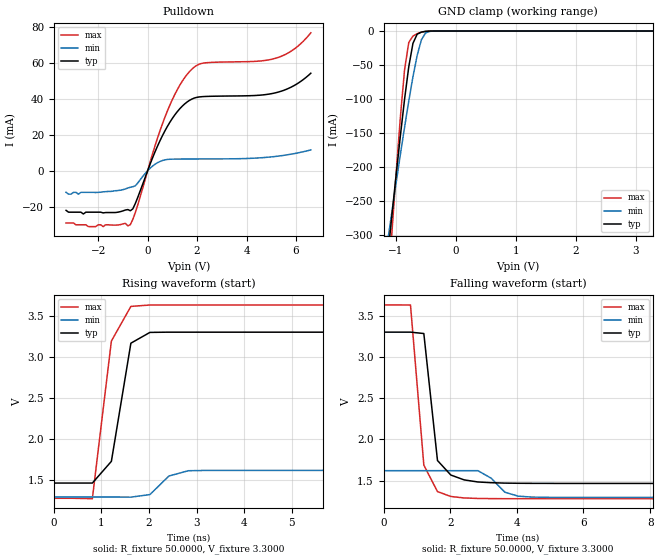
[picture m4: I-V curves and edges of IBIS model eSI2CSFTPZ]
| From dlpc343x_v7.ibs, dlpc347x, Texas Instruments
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[Model]  eSI2CSFTPZ
Model_type I/O_open_drain
Polarity   Non-Inverting
Enable   Active-High
Vinl =   0.0V
Vinh =   3.3000V
Vmeas =  1.6500V
Rref =   500.0000
Vref =   3.3V
C_comp   2.1049pF   1.8316pF   1.9628pF
[Temperature Range]   25.0000   0.1050k   -30.0000
[Pullup Reference]   3.3000V   1.6200V   3.6300V
[Pulldown Reference]   0.0V   0.0V   0.0V
[POWER Clamp Reference]   3.3000V   1.6200V   3.6300V
[GND Clamp Reference]   0.0V   0.0V   0.0V
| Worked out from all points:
|   slope of the pulldown table from 0 to 0.495 V, typ, clamps not added: 29.9 ohm
|   GND clamp passes 1 mA (typ) near -0.53 V on its own axis
|   rising waveform, R_fixture 50.0000, V_fixture 3.3000: 20-80 % time 314ps typ, 364ps min, 294ps max; typ from 1.47 V to 3.3 V
|   falling waveform, R_fixture 50.0000, V_fixture 3.3000: 20-80 % time 293ps typ, 521ps min, 290ps max; typ from 3.3 V to 1.47 V
[Pulldown]
|Voltage   I(typ)   I(min)   I(max)
-3.3V     -22mA      -12mA      -29mA
-2.6V     -24mA      -12mA      -30mA
-700mV    -22.2mA    -9.18mA    -29.9mA
-500mV    -18.24mA   -8.389mA   -23.3mA
200mV     7.182mA    2.577mA    9.472mA
800mV     24.62mA    6.256mA    33.2mA
1.4V      35.83mA    6.49mA     49.68mA
1.9V      40.39mA    6.522mA    57.65mA
2.3V      41.18mA    6.538mA    59.81mA
5.2V      43.33mA    7.976mA    62.52mA
5.9V      47.07mA    9.425mA    67.23mA
6.6V      54.11mA    11.53mA    76.52mA
[GND_clamp]
|Voltage   I(typ)   I(min)   I(max)
-3.3V     -2.377A    -1.75A     -3.463A
-1.13V    -331.8mA   -309mA     -386.6mA
-1.06V    -271.2mA   -265.9mA   -296.4mA
-920mV    -154.8mA   -182.1mA   -127.4mA
-850mV    -100.8mA   -141.9mA   -57.27mA
-780mV    -52.76mA   -103.3mA   -16.94mA
-710mV    -18.12mA   -67.29mA   -7.429mA
-640mV    -4.691mA   -35.84mA   -3.902mA
-570mV    -1.611mA   -13.05mA   -1.639mA
-500mV    -496.8uA   -2.841mA   -454.2uA
-430mV    -94.47uA   -468.6uA   -64.45uA
3.28V     437.5pA    3.787nA    75.03pA
[Ramp]
| variable   typ   min   max
dV/dt_r  1.1010/0.3067n   0.1944/0.3629n   1.4100/0.2944n
dV/dt_f  1.1010/0.2860n   0.1944/0.5109n   1.4100/0.2904n
R_load = 50.0000
[Rising Waveform]
R_fixture= 50.0000
V_fixture= 3.3000
V_fixture_min= 1.6200
V_fixture_max= 3.6300
|time   V(typ)   V(min)   V(max)
0s        1.465V     1.296V     1.28V
810ps     1.465V     1.296V     1.275V
1.21ns    1.729V     1.296V     3.191V
1.62ns    3.165V     1.294V     3.612V
2.02ns    3.296V     1.325V     3.629V
2.42ns    3.299V     1.551V     3.629V
2.83ns    3.299V     1.615V     3.629V
3.23ns    3.299V     1.619V     3.629V
40ns      3.3V       1.62V      3.63V
[Falling Waveform]
R_fixture= 50.0000
V_fixture= 3.3000
V_fixture_min= 1.6200
V_fixture_max= 3.6300
|time   V(typ)   V(min)   V(max)
0s        3.3V       1.62V      3.63V
810ps     3.3V       1.62V      3.629V
1.21ns    3.283V     1.62V      1.687V
1.62ns    1.743V     1.62V      1.366V
2.02ns    1.567V     1.62V      1.307V
2.83ns    1.483V     1.62V      1.283V
3.23ns    1.474V     1.529V     1.281V
3.64ns    1.469V     1.359V     1.28V
4.44ns    1.466V     1.3V       1.28V
40ns      1.465V     1.296V     1.28V
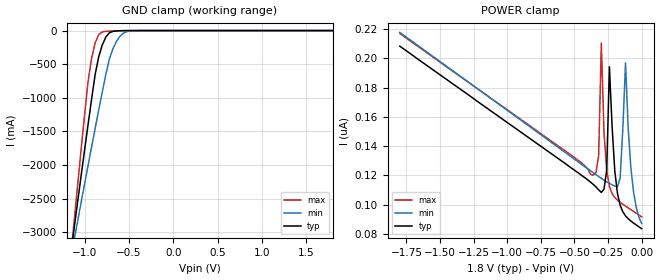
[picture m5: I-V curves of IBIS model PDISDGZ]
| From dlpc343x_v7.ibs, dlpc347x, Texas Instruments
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[Model]  PDISDGZ
Model_type Input
Polarity   Non-Inverting
Vinl =   0.6300V
Vinh =   1.1700V
C_comp   3.3681pF   3.2595pF   3.5090pF
[Temperature Range]   25.0000   0.1250k   -40.0000
[Voltage Range]   1.8000V   1.6200V   1.9800V
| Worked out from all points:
|   GND clamp passes 1 mA (typ) near -0.54 V on its own axis
[GND_clamp]
|Voltage   I(typ)   I(min)   I(max)
-1.8V     -9.929A    -8.053A    -12.56A
-1.16V    -3.375A    -3.424A    -3.437A
-1.12V    -2.974A    -3.138A    -2.882A
-1.08V    -2.574A    -2.854A    -2.333A
-960mV    -1.399A    -2.009A    -757mA
-920mV    -1.019A    -1.731A    -410.8mA
-880mV    -652.7mA   -1.455A    -184.5mA
-800mV    -215.1mA   -916mA     -20.59mA
-720mV    -33.9mA    -424.5mA   -7.959mA
-680mV    -11.5mA    -271.8mA   -5.67mA
-520mV    -735.3uA   -14.09mA   -620.1uA
1.8V      83.53nA    112.1nA    80.6nA
[POWER_clamp]
|Voltage   I(typ)   I(min)   I(max)
-1.8V     208.3nA    217.7nA    217nA
-360mV    113.8nA    121.8nA    120.1nA
-320mV    110.1nA    119.2nA    133.5nA
-300mV    108.3nA    117.9nA    210.4nA
-280mV    110.6nA    116.7nA    148.8nA
-260mV    123.6nA    115.6nA    123.4nA
-240mV    194.2nA    114.5nA    112.5nA
-200mV    123nA      112.7nA    104.8nA
-160mV    99.55nA    118.3nA    101.5nA
-120mV    92.28nA    196.8nA    98.96nA
-80mV     88.74nA    124.8nA    96.5nA
0V        83.53nA    87.07nA    91.6nA
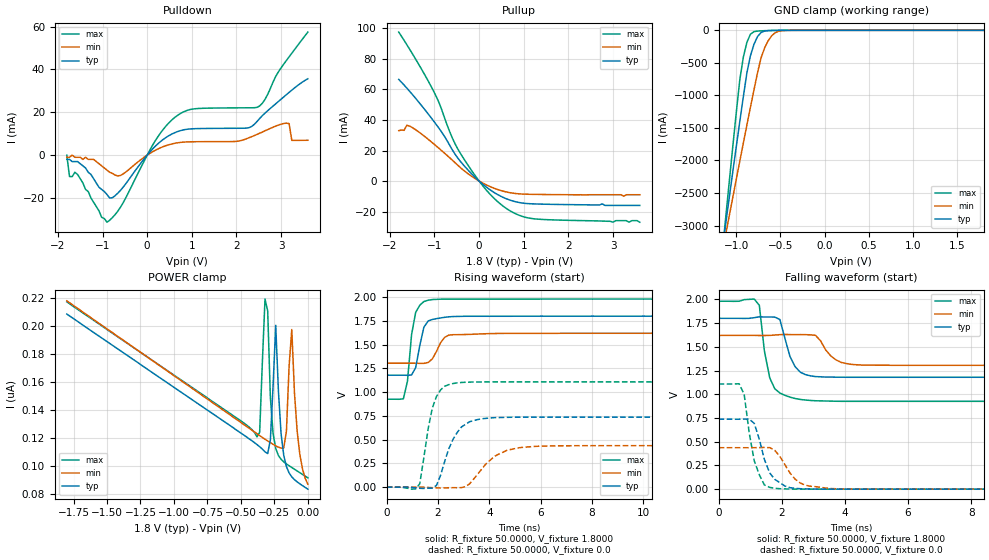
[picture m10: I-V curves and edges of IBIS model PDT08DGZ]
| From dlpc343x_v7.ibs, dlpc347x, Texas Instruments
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[Model]  PDT08DGZ
Model_type 3-state
Polarity   Non-Inverting
Enable   Active-Low
Vmeas =  0.9000V
Cref =   50.0000pF
Rref =   1.0000M
Vref =   0.0V
C_comp   3.1400pF   3.0336pF   3.2859pF
[Temperature Range]   25.0000   0.1250k   -40.0000
[Voltage Range]   1.8000V   1.6200V   1.9800V
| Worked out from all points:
|   slope of the pulldown table from 0 to 0.27 V, typ, clamps not added: 46.3 ohm
|   slope of the pullup table from 0 to 0.27 V, typ, clamps not added: 43.3 ohm
|   GND clamp passes 1 mA (typ) near -0.54 V on its own axis
|   rising waveform, R_fixture 50.0000, V_fixture 1.8000: 20-80 % time 282ps typ, 387ps min, 265ps max; typ from 1.18 V to 1.8 V
|   rising waveform, R_fixture 50.0000, V_fixture 0.0: 20-80 % time 664ps typ, 981ps min, 454ps max; typ from 0 V to 0.737 V
|   falling waveform, R_fixture 50.0000, V_fixture 1.8000: 20-80 % time 373ps typ, 456ps min, 324ps max; typ from 1.8 V to 1.18 V
|   falling waveform, R_fixture 50.0000, V_fixture 0.0: 20-80 % time 447ps typ, 565ps min, 359ps max; typ from 0.737 V to 0 V
[Pulldown]
|Voltage   I(typ)   I(min)   I(max)
-1.8V     -2mA       -1mA       0A
-1.74V    -2mA       -1mA       -10mA
-1.56V    -3mA       -1mA       -9mA
-900mV    -18.4mA    -7mA       -31.3mA
-600mV    -16.49mA   -9.49mA    -24.39mA
540mV     9.714mA    5.159mA    16.17mA
1.02V     12.31mA    6.241mA    21.52mA
2.52V     17.11mA    10.22mA    22.95mA
3.12V     28.25mA    14.93mA    44.21mA
3.18V     29.3mA     14.7mA     45.89mA
3.24V     30.34mA    6.887mA    47.56mA
3.6V      35.65mA    6.947mA    57.44mA
[Pullup]
|Voltage   I(typ)   I(min)   I(max)
-1.8V     66.61mA    33.02mA    97.64mA
-1.68V    62.91mA    33.23mA    92.2mA
-1.62V    60.96mA    36.5mA     89.41mA
-1.5V     56.93mA    35.1mA     83.71mA
-960mV    37.03mA    22.95mA    55.42mA
-660mV    23.52mA    15.27mA    32.42mA
-480mV    15.15mA    10.43mA    21.16mA
60mV      -1.545mA   -990.4uA   -2.299mA
480mV     -9.897mA   -6.175mA   -15.13mA
840mV     -13.75mA   -8.275mA   -21.76mA
1.2V      -14.98mA   -8.744mA   -24.67mA
3.6V      -16mA      -9mA       -27mA
[GND_clamp]
|Voltage   I(typ)   I(min)   I(max)
-1.8V     -9.929A    -8.053A    -12.56A
-1.16V    -3.375A    -3.424A    -3.437A
-1.12V    -2.974A    -3.138A    -2.882A
-1.08V    -2.574A    -2.854A    -2.333A
-960mV    -1.399A    -2.009A    -757mA
-920mV    -1.019A    -1.731A    -410.8mA
-880mV    -652.7mA   -1.455A    -184.5mA
-800mV    -215.1mA   -916mA     -20.59mA
-720mV    -33.9mA    -424.5mA   -7.959mA
-680mV    -11.5mA    -271.8mA   -5.67mA
-520mV    -735.3uA   -14.09mA   -620.1uA
1.8V      83.53nA    112.9nA    80.6nA
[POWER_clamp]
|Voltage   I(typ)   I(min)   I(max)
-1.8V     208.3nA    217.7nA    217nA
-380mV    115.3nA    123nA      120.8nA
-360mV    113.8nA    121.7nA    124nA
-320mV    110.1nA    119.1nA    219nA
-300mV    108.9nA    117.9nA    210.6nA
-280mV    118.6nA    116.7nA    148.9nA
-240mV    200.3nA    114.4nA    112.5nA
-200mV    123nA      112.8nA    104.8nA
-160mV    99.55nA    125nA      101.5nA
-120mV    92.28nA    197.3nA    98.96nA
-80mV     88.74nA    124.9nA    96.5nA
0V        83.53nA    87.07nA    91.6nA
[Ramp]
| variable   typ   min   max
dV/dt_r  0.4421/0.6537n   0.2621/0.9702n   0.6648/0.4436n
dV/dt_f  0.3726/0.3726n   0.1890/0.4459n   0.6326/0.3139n
R_load = 50.0000
[Rising Waveform]
R_fixture= 50.0000
V_fixture= 1.8000
V_fixture_min= 1.6200
V_fixture_max= 1.9800
L_fixture= 0.0H
C_fixture= 0.0F
|time   V(typ)   V(min)   V(max)
0s        1.179V     1.305V     925.6mV
650ps     1.179V     1.305V     929.1mV
810ps     1.177V     1.305V     1.115V
970ps     1.181V     1.305V     1.605V
1.13ns    1.258V     1.305V     1.84V
1.45ns    1.684V     1.303V     1.954V
1.62ns    1.75V      1.313V     1.968V
2.26ns    1.788V     1.577V     1.979V
2.59ns    1.796V     1.605V     1.979V
16ns      1.8V       1.62V      1.98V
[Rising Waveform]
R_fixture= 50.0000
V_fixture= 0.0
V_fixture_min= 0.0
V_fixture_max= 0.0
L_fixture= 0.0H
C_fixture= 0.0F
|time   V(typ)   V(min)   V(max)
0s        1.388uV    1.828uV    1.142uV
1.13ns    -7.397mV   183.9uV    -18.52mV
1.29ns    -11.85mV   324.3uV    36.41mV
1.78ns    -10.45mV   -5.142mV   833.2mV
2.1ns     124mV      -8.392mV   1.023V
2.59ns    505.3mV    -5.347mV   1.091V
3.23ns    688.6mV    34.52mV    1.106V
4.2ns     731.5mV    322.7mV    1.108V
5.17ns    736.3mV    415.2mV    1.108V
16ns      736.9mV    436.8mV    1.108V
[Falling Waveform]
R_fixture= 50.0000
V_fixture= 1.8000
V_fixture_min= 1.6200
V_fixture_max= 1.9800
L_fixture= 0.0H
C_fixture= 0.0F
|time   V(typ)   V(min)   V(max)
0s        1.8V       1.62V      1.98V
1.29ns    1.816V     1.619V     1.937V
1.45ns    1.814V     1.619V     1.457V
1.62ns    1.814V     1.62V      1.172V
1.94ns    1.788V     1.628V     1.013V
2.42ns    1.292V     1.628V     955.6mV
3.07ns    1.186V     1.621V     931.5mV
3.72ns    1.18V      1.362V     926.4mV
4.36ns    1.179V     1.311V     925.7mV
16ns      1.179V     1.305V     925.6mV
[Falling Waveform]
R_fixture= 50.0000
V_fixture= 0.0
V_fixture_min= 0.0
V_fixture_max= 0.0
L_fixture= 0.0H
C_fixture= 0.0F
|time   V(typ)   V(min)   V(max)
0s        736.9mV    436.8mV    1.108V
650ps     736.7mV    436.6mV    1.111V
810ps     738.7mV    436.6mV    998.8mV
970ps     738.1mV    436.6mV    592mV
1.13ns    693mV      436.8mV    297.9mV
1.45ns    313.4mV    439.5mV    44.67mV
1.62ns    170.6mV    437.4mV    18.63mV
2.59ns    4.647mV    64mV       417.7uV
3.39ns    380.7uV    11.98mV    10.22uV
16ns      -760nV     0V         -1.275uV
